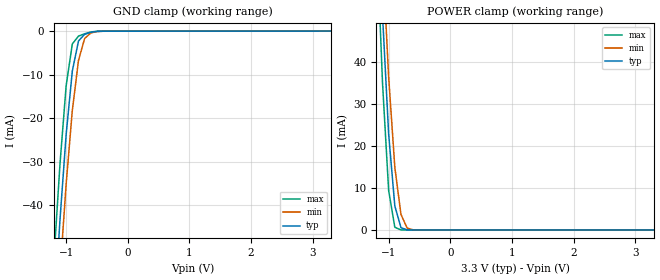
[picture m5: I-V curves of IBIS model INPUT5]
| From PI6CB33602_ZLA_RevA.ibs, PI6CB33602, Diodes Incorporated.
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[Model] INPUT5
Model_type Input
Vinl = 825mV
Vinh = 2.75V
| variable   typ   min   max
C_comp   0.628pF   0.627pF   0.629pF
[Voltage Range]   3.3V   3.135V   3.465V
[GND Clamp Reference]   0.000V   0.000V   0.000V
[POWER Clamp Reference]   3.3V   3.135V   3.465V
[temperature range]   25   85   -40
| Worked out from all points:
|   GND clamp passes 1 mA (typ) near -0.72 V on its own axis
|   POWER clamp passes 1 mA (typ) near -0.81 V on its own axis
[GND Clamp]
| Voltage   I(typ)   I(min)   I(max)
-3.3V     -806mA     -784mA     -851mA
-1.2V     -65.6mA    -77.9mA    -52.7mA
-1.1V     -43.3mA    -55.5mA    -30.5mA
-1V       -23.7mA    -35.1mA    -12.5mA
-900mV    -9.15mA    -18.2mA    -2.93mA
-800mV    -2.24mA    -6.72mA    -1.13mA
-700mV    -702uA     -1.66mA    -594uA
-600mV    -266uA     -406uA     -185uA
-500mV    -41.5uA    -86.4uA    -13.4uA
3.3V      27.3uA     28.7uA     25.2uA
[POWER Clamp]   |Note: Vtable = Vcc - Voutput
| Voltage   I(typ)   I(min)   I(max)
-3.3V     1.02A      977mA      1.08A
-1.2V     86.3mA     99mA       71.7mA
-1.1V     51.3mA     65.5mA     35.1mA
-1V       22.8mA     36.4mA     9.39mA
-900mV    5.72mA     14.9mA     638uA
-800mV    544uA      3.68mA     8.25uA
-700mV    18.7uA     441uA      62.5nA
-600mV    428nA      26.6uA     460pA
3.3V      -9.9pA     -97pA      -9.41pA
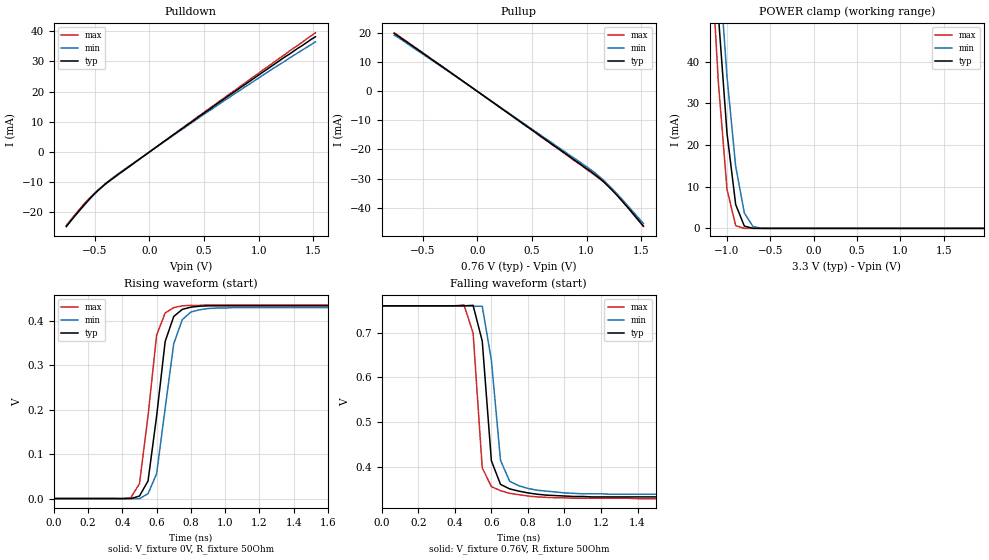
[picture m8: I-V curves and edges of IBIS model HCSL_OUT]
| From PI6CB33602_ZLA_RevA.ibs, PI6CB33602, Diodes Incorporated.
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[Model]  HCSL_OUT
Model_type  Output
Vmeas =  0.2
Vref = 0
Rref = 50
|Variable   typ   min   max
C_comp   1.41p   1.40p  1.42p
|Variable   typ   min   max
[Voltage Range]   0.76   0.76   0.76
[Temperature Range]   25   85   -40
[POWER Clamp Reference]   3.3   3.135   3.465
[Pullup Reference]   0.76   0.76   0.76
[Pulldown Reference]   0   0   0
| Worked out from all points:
|   slope of the pulldown table from 0 to 0.114 V, typ, clamps not added: 38.5 ohm
|   slope of the pullup table from 0 to 0.114 V, typ, clamps not added: 37.6 ohm
|   POWER clamp passes 1 mA (typ) near -0.81 V on its own axis
|   falling waveform, V_fixture 0.76V, R_fixture 50Ohm: 20-80 % time 48ps typ, 63.8ps min, 42.9ps max; typ from 0.76 V to 0.331 V
|   rising waveform, V_fixture 0V, R_fixture 50Ohm: 20-80 % time 81.9ps typ, 88.2ps min, 77.2ps max; typ from 0 V to 0.433 V
[Power clamp]
| Voltage   I(typ)   I(min)  I(max)
-3.3V     1.02A      977mA      1.08A
-1.2V     86.3mA     99mA       71.7mA
-1.1V     51.3mA     65.5mA     35.1mA
-1V       22.8mA     36.4mA     9.39mA
-900mV    5.72mA     14.9mA     638uA
-800mV    544uA      3.68mA     8.25uA
-700mV    18.7uA     441uA      62.5nA
-600mV    428nA      26.6uA     447pA
6.6V      -19.8pA    -19.9pA    -19.8pA
[Pulldown]   |Note: Vtable = Vcc - Voutput
| Voltage   I(typ)   I(min)  I(max)
-760mV    -24.7mA    -24.6mA    -24.3mA
-560mV    -16.1mA    -16.1mA    -15.7mA
-480mV    -13.1mA    -13.1mA    -12.9mA
-400mV    -10.5mA    -10.4mA    -10.6mA
-320mV    -8.33mA    -8.14mA    -8.43mA
680mV     17.5mA     16.9mA     17.8mA
1.12V     28.5mA     27.4mA     29.2mA
1.52V     38.2mA     36.5mA     39.5mA
[Pullup]   |Note: Vtable = Vcc - Voutput
| Voltage   I(typ)   I(min)  I(max)
-760mV    19.9mA     19.3mA     20.1mA
-120mV    3.18mA     3.11mA     3.21mA
1.08V     -28.7mA    -28.1mA    -29mA
1.16V     -31.2mA    -30.7mA    -31.3mA
1.24V     -34.2mA    -33.7mA    -34.1mA
1.32V     -37.5mA    -36.9mA    -37.4mA
1.52V     -46.3mA    -45.4mA    -46.5mA
[Falling Waveform]
V_fixture = 0.76V
V_fixture_min = 0.76V
V_fixture_max = 0.76V
R_fixture = 50Ohm
C_fixture = 0F
|   Time   V(typ)   V(min)   V(max)
0s        760mV      760mV      760mV
450ps     760mV      760mV      762mV
500ps     761mV      759mV      699mV
550ps     681mV      759mV      397mV
600ps     413mV      638mV      355mV
650ps     360mV      414mV      346mV
700ps     350mV      367mV      340mV
850ps     338mV      347mV      332mV
1.1ns     333mV      339mV      329mV
4.95ns    331mV      337mV      328mV
[Rising Waveform]
V_fixture = 0V
V_fixture_min = 0V
V_fixture_max = 0V
R_fixture = 50Ohm
C_fixture = 0F
|   Time   V(typ)   V(min)   V(max)
0s        0V         659nV      0V
450ps     -79.6uV    -191uV     2.31mV
500ps     5.64mV     -341uV     33.4mV
550ps     39.5mV     11mV       186mV
600ps     185mV      55.9mV     367mV
650ps     353mV      203mV      417mV
700ps     409mV      348mV      429mV
800ps     430mV      419mV      434mV
950ps     433mV      428mV      435mV
4.95ns    433mV      429mV      435mV
[Ramp]
|   typ   min   max
dV/dt_r   0.260/0.07E-12   0.259/0.06E-12   0.261/0.08E-12
dV/dt_f   0.257/0.05E-12   0.256/0.04E-12   0.258/0.06E-12
R_load =   50.0000
